One B-rep face of a CAD part: STEP entity #761.
In plain terms, the planar face has unit normal (1, 0, 0).
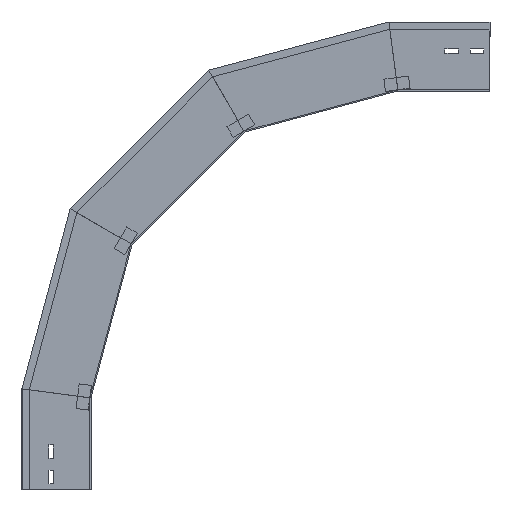
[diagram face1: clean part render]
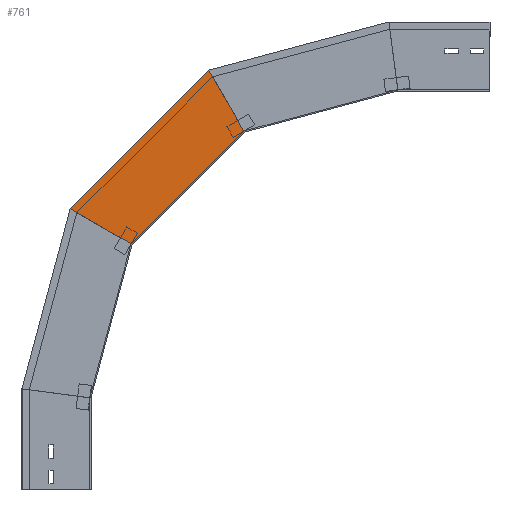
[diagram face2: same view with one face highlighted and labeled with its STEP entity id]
Its self-contained STEP definition (entity closure, numbers rounded to 3 decimals):
#4 = VECTOR ( 'NONE', #1297, 1000. ) ;
#65 = EDGE_CURVE ( 'NONE', #1084, #1653, #215, .T. ) ;
#118 = CARTESIAN_POINT ( 'NONE',  ( 0., -287.996, 517.807 ) ) ;
#140 = VERTEX_POINT ( 'NONE', #1645 ) ;
#209 = PLANE ( 'NONE',  #434 ) ;
#215 = LINE ( 'NONE', #1364, #1039 ) ;
#256 = LINE ( 'NONE', #118, #1199 ) ;
#258 = CARTESIAN_POINT ( 'NONE',  ( 0., -67.034, 400.175 ) ) ;
#434 = AXIS2_PLACEMENT_3D ( 'NONE', #1835, #494, #632 ) ;
#451 = ORIENTED_EDGE ( 'NONE', *, *, #640, .F. ) ;
#494 = DIRECTION ( 'NONE',  ( 1., 0., 0. ) ) ;
#521 = ORIENTED_EDGE ( 'NONE', *, *, #65, .F. ) ;
#632 = DIRECTION ( 'NONE',  ( 0., 0., -1. ) ) ;
#634 = ORIENTED_EDGE ( 'NONE', *, *, #856, .T. ) ;
#640 = EDGE_CURVE ( 'NONE', #1653, #140, #1034, .T. ) ;
#656 = DIRECTION ( 'NONE',  ( 0., -0.866, -0.5 ) ) ;
#761 = ADVANCED_FACE ( 'NONE', ( #1686 ), #209, .T. ) ;
#856 = EDGE_CURVE ( 'NONE', #1390, #140, #256, .T. ) ;
#861 = CARTESIAN_POINT ( 'NONE',  ( 0., -43.517, 376.657 ) ) ;
#1034 = LINE ( 'NONE', #861, #4 ) ;
#1039 = VECTOR ( 'NONE', #656, 1000. ) ;
#1045 = EDGE_CURVE ( 'NONE', #1084, #1390, #1488, .T. ) ;
#1065 = ORIENTED_EDGE ( 'NONE', *, *, #1045, .T. ) ;
#1084 = VERTEX_POINT ( 'NONE', #1312 ) ;
#1161 = DIRECTION ( 'NONE',  ( 0., -0.707, 0.707 ) ) ;
#1199 = VECTOR ( 'NONE', #1866, 1000. ) ;
#1297 = DIRECTION ( 'NONE',  ( 0., -0.707, 0.707 ) ) ;
#1312 = CARTESIAN_POINT ( 'NONE',  ( 0., 33.831, 458.409 ) ) ;
#1364 = CARTESIAN_POINT ( 'NONE',  ( 0., -128.762, 364.536 ) ) ;
#1390 = VERTEX_POINT ( 'NONE', #1486 ) ;
#1486 = CARTESIAN_POINT ( 'NONE',  ( 0., -191.941, 684.18 ) ) ;
#1488 = LINE ( 'NONE', #1779, #1553 ) ;
#1553 = VECTOR ( 'NONE', #1161, 1000. ) ;
#1645 = CARTESIAN_POINT ( 'NONE',  ( 0., -250.175, 583.315 ) ) ;
#1653 = VERTEX_POINT ( 'NONE', #258 ) ;
#1686 = FACE_OUTER_BOUND ( 'NONE', #1883, .T. ) ;
#1779 = CARTESIAN_POINT ( 'NONE',  ( 0., 36.033, 456.207 ) ) ;
#1835 = CARTESIAN_POINT ( 'NONE',  ( 0., -43.517, 376.657 ) ) ;
#1866 = DIRECTION ( 'NONE',  ( 0., -0.5, -0.866 ) ) ;
#1883 = EDGE_LOOP ( 'NONE', ( #1065, #634, #451, #521 ) ) ;
